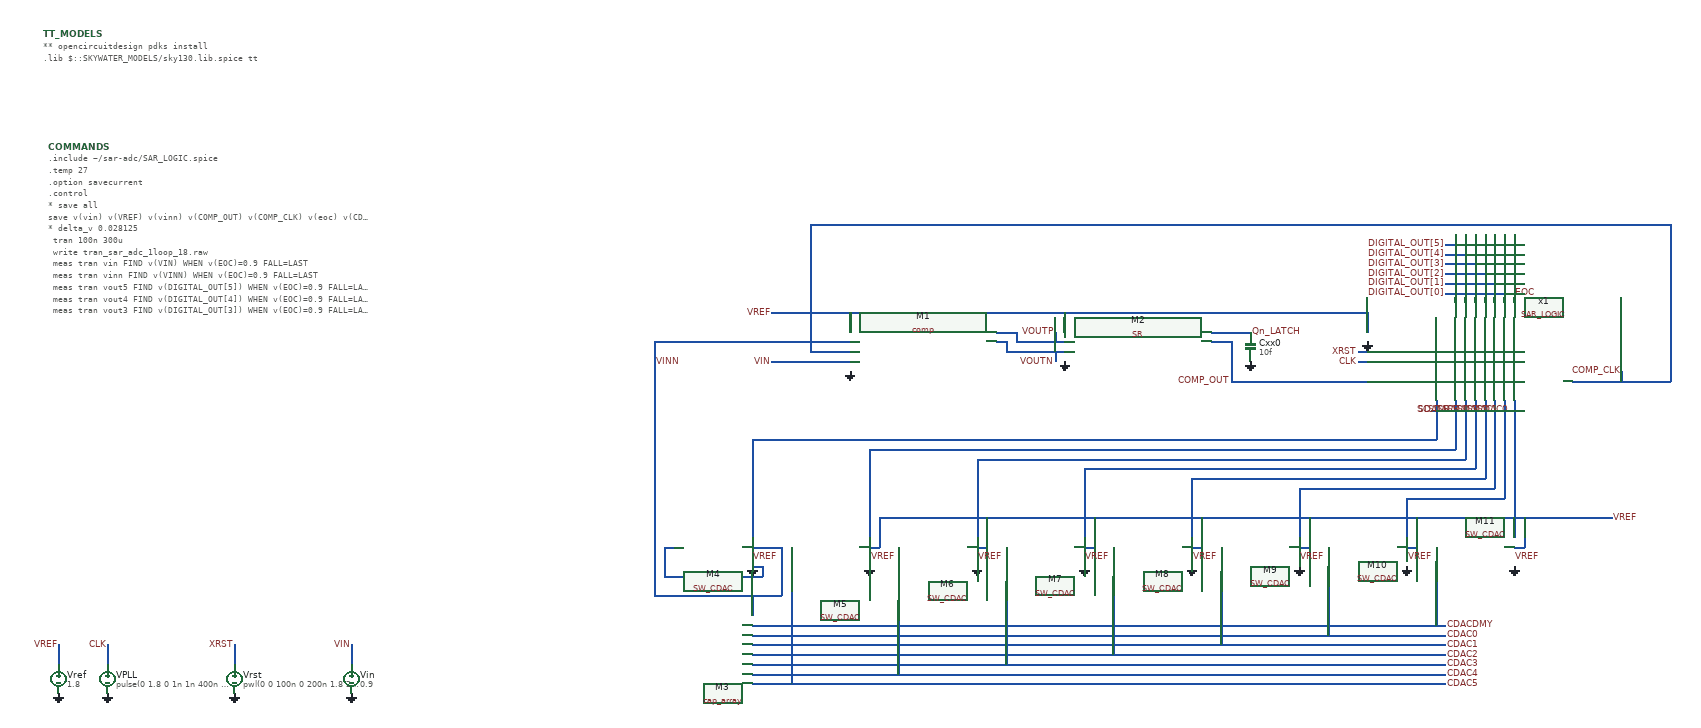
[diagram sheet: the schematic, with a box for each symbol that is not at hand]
v {xschem version=3.4.8RC file_version=1.3}
G {}
K {}
V {}
S {}
F {}
E {}
N 60 -300 60 -260 {
lab=VREF}
N 160 -300 160 -260 {
lab=CLK}
N 420 -300 420 -260 {
lab=XRST}
N 660 -300 660 -260 {
lab=VIN}
N 2460 -840 2740 -840 {
lab=COMP_OUT}
N 2720 -880 2740 -880 {
lab=CLK}
N 2720 -900 2740 -900 {
lab=XRST}
N 3040 -800 3040 -710 {
lab=SDAC0}
N 3030 -780 3040 -780 {
lab=SDAC0}
N 3020 -800 3020 -710 {
lab=SDAC1}
N 3010 -780 3020 -780 {
lab=SDAC1}
N 3000 -800 3000 -710 {
lab=SDAC2}
N 2990 -780 3000 -780 {
lab=SDAC2}
N 2980 -800 2980 -710 {
lab=SDAC3}
N 2970 -780 2980 -780 {
lab=SDAC3}
N 2960 -800 2960 -710 {
lab=SDAC4}
N 2950 -780 2960 -780 {
lab=SDAC4}
N 2940 -800 2940 -710 {
lab=SDAC5}
N 2930 -780 2940 -780 {
lab=SDAC5}
N 2920 -800 2920 -710 {
lab=SDAC6}
N 2910 -780 2920 -780 {
lab=SDAC6}
N 2880 -800 2880 -720 {
lab=SC}
N 2870 -780 2880 -780 {
lab=SC}
N 3160 -840 3360 -840 {
lab=COMP_CLK}
N 3260 -860 3260 -840 {
lab=COMP_CLK}
N 1980 -940 2020 -940 {
lab=VOUTP}
N 1980 -920 2000 -920 {
lab=VOUTN}
N 1480 -340 2900 -340 {
lab=CDACDMY}
N 1480 -320 2900 -320 {
lab=CDAC0}
N 1480 -300 2900 -300 {
lab=CDAC1}
N 1480 -280 2900 -280 {
lab=CDAC2}
N 1480 -260 2900 -260 {
lab=CDAC3}
N 1480 -240 2900 -240 {
lab=CDAC4}
N 1480 -220 2900 -220 {
lab=CDAC5}
N 1720 -700 2920 -700 {
lab=SDAC6}
N 1720 -700 1720 -520 {
lab=SDAC6}
N 1940 -680 1940 -520 {
lab=SDAC5}
N 1940 -680 2940 -680 {
lab=SDAC5}
N 2160 -660 2960 -660 {
lab=SDAC4}
N 2160 -660 2160 -520 {
lab=SDAC4}
N 2380 -640 2380 -520 {
lab=SDAC3}
N 2380 -640 2980 -640 {
lab=SDAC3}
N 2600 -620 3000 -620 {
lab=SDAC2}
N 2600 -620 2600 -520 {
lab=SDAC2}
N 2820 -600 2820 -520 {
lab=SDAC1}
N 3040 -710 3040 -520 {
lab=SDAC0}
N 1480 -720 2880 -720 {
lab=SC}
N 1480 -720 1480 -520 {
lab=SC}
N 1300 -500 1320 -500 {
lab=GND}
N 1300 -500 1300 -440 {
lab=GND}
N 1300 -440 1500 -440 {
lab=GND}
N 1500 -460 1500 -440 {
lab=GND}
N 1480 -460 1500 -460 {
lab=GND}
N 1480 -400 1480 -360 {
lab=VINN}
N 1280 -400 1480 -400 {
lab=VINN}
N 1280 -920 1280 -400 {
lab=VINN}
N 1280 -920 1680 -920 {
lab=VINN}
N 1480 -500 1540 -500 {
lab=VINN}
N 1540 -500 1540 -400 {
lab=VINN}
N 1480 -400 1540 -400 {
lab=VINN}
N 2820 -600 3020 -600 {
lab=SDAC1}
N 1600 -900 1680 -900 {
lab=COMP_CLK}
N 1600 -1160 1600 -900 {
lab=COMP_CLK}
N 1600 -1160 3360 -1160 {
lab=COMP_CLK}
N 3360 -1160 3360 -840 {
lab=COMP_CLK}
N 2420 -920 2460 -920 {
lab=COMP_OUT}
N 2460 -920 2460 -840 {
lab=COMP_OUT}
N 2420 -940 2500 -940 {
lab=Qn_LATCH}
N 1740 -560 3240 -560 {
lab=VREF}
N 1720 -500 1740 -500 {
lab=VREF}
N 1740 -560 1740 -500 {
lab=VREF}
N 1940 -500 1960 -500 {
lab=VREF}
N 1960 -560 1960 -500 {
lab=VREF}
N 2160 -500 2180 -500 {
lab=VREF}
N 2180 -560 2180 -500 {
lab=VREF}
N 2380 -500 2400 -500 {
lab=VREF}
N 2400 -560 2400 -500 {
lab=VREF}
N 2600 -500 2620 -500 {
lab=VREF}
N 2620 -560 2620 -500 {
lab=VREF}
N 2820 -500 2840 -500 {
lab=VREF}
N 2840 -560 2840 -500 {
lab=VREF}
N 3040 -500 3060 -500 {
lab=VREF}
N 3060 -560 3060 -500 {
lab=VREF}
N 1520 -880 1680 -880 {
lab=VIN}
N 2100 -900 2100 -880 {
lab=VOUTN}
N 2100 -940 2100 -920 {
lab=VOUTP}
N 2020 -940 2020 -920 {
lab=VOUTP}
N 2920 -710 2920 -700 {
lab=SDAC6}
N 2940 -710 2940 -680 {
lab=SDAC5}
N 2960 -710 2960 -660 {
lab=SDAC4}
N 2980 -710 2980 -640 {
lab=SDAC3}
N 3000 -710 3000 -620 {
lab=SDAC2}
N 3020 -710 3020 -600 {
lab=SDAC1}
N 2000 -500 2000 -260 {
lab=CDAC3}
N 1780 -500 1780 -240 {
lab=CDAC4}
N 1560 -500 1560 -220 {
lab=CDAC5}
N 2920 -1140 2920 -1000 {
lab=DIGITAL_OUT[5]}
N 2900 -1120 2920 -1120 {
lab=DIGITAL_OUT[5]}
N 2900 -1100 2940 -1100 {
lab=DIGITAL_OUT[4]}
N 2900 -1080 2960 -1080 {
lab=DIGITAL_OUT[3]}
N 2900 -1060 2980 -1060 {
lab=DIGITAL_OUT[2]}
N 2900 -1040 3000 -1040 {
lab=DIGITAL_OUT[1]}
N 2900 -1020 3020 -1020 {
lab=DIGITAL_OUT[0]}
N 2940 -1140 2940 -1000 {
lab=DIGITAL_OUT[4]}
N 2960 -1140 2960 -1000 {
lab=DIGITAL_OUT[3]}
N 2980 -1140 2980 -1000 {
lab=DIGITAL_OUT[2]}
N 3000 -1140 3000 -1000 {
lab=DIGITAL_OUT[1]}
N 3020 -1140 3020 -1000 {
lab=DIGITAL_OUT[0]}
N 3040 -1140 3040 -1000 {
lab=EOC}
N 2000 -920 2000 -900 {
lab=VOUTN}
N 2000 -900 2120 -900 {
lab=VOUTN}
N 2020 -920 2120 -920 {
lab=VOUTP}
N 2220 -500 2220 -280 {lab=CDAC2}
N 2440 -500 2440 -300 {lab=CDAC1}
N 2660 -500 2660 -320 {lab=CDAC0}
N 2880 -500 2880 -340 {lab=CDACDMY}
N 1520 -980 2740 -980 {lab=VREF}
N 2740 -980 2740 -940 {lab=VREF}
N 2120 -980 2120 -940 {lab=VREF}
N 1680 -980 1680 -940 {lab=VREF}
C {devices/vsource.sym} 60 -230 0 0 {name=Vref value=1.8 savecurrent=false}
C {devices/gnd.sym} 160 -200 0 0 {name=l2 lab=GND}
C {devices/gnd.sym} 60 -200 0 0 {name=l3 lab=GND}
C {devices/simulator_commands_shown.sym} 40 -1320 0 0 {name=COMMANDS
simulator=ngspice
only_toplevel=false 
value=".include ~/sar-adc/SAR_LOGIC.spice
.temp 27
.option savecurrent
.control
* save all
save v(vin) v(VREF) v(vinn) v(COMP_OUT) v(COMP_CLK) v(eoc) v(CDACDMY) v(CDAC0) v(CDAC1) v(CDAC2) v(CDAC3) v(CDAC4) v(CDAC5) v(digital_out[5]) v(digital_out[4]) v(digital_out[3]) v(digital_out[2]) v(digital_out[1]) v(digital_out[0])

* delta_v 0.028125

	tran 100n 300u
	write tran_sar_adc_1loop_18.raw
	meas tran vin FIND v(VIN) WHEN v(EOC)=0.9 FALL=LAST
	meas tran vinn FIND v(VINN) WHEN v(EOC)=0.9 FALL=LAST
	meas tran vout5 FIND v(DIGITAL_OUT[5]) WHEN v(EOC)=0.9 FALL=LAST
	meas tran vout4 FIND v(DIGITAL_OUT[4]) WHEN v(EOC)=0.9 FALL=LAST
	meas tran vout3 FIND v(DIGITAL_OUT[3]) WHEN v(EOC)=0.9 FALL=LAST
	meas tran vout2 FIND v(DIGITAL_OUT[2]) WHEN v(EOC)=0.9 FALL=LAST
	meas tran vout1 FIND v(DIGITAL_OUT[1]) WHEN v(EOC)=0.9 FALL=LAST
	meas tran vout0 FIND v(DIGITAL_OUT[0]) WHEN v(EOC)=0.9 FALL=LAST
	print vin >> tran_sar_adc_1loop_out_typ.txt
*	print vinn >> tran_sar_adc_1loop_out_typ.txt
	print vout5 >> tran_sar_adc_1loop_out_typ.txt
	print vout4 >> tran_sar_adc_1loop_out_typ.txt
	print vout3 >> tran_sar_adc_1loop_out_typ.txt
	print vout2 >> tran_sar_adc_1loop_out_typ.txt
	print vout1 >> tran_sar_adc_1loop_out_typ.txt
	print vout0 >> tran_sar_adc_1loop_out_typ.txt

.endc
"}
C {devices/lab_pin.sym} 160 -300 0 0 {name=p2 sig_type=std_logic lab=CLK}
C {devices/lab_pin.sym} 420 -300 0 0 {name=p9 sig_type=std_logic lab=XRST}
C {devices/gnd.sym} 420 -200 0 0 {name=l1 lab=GND}
C {devices/lab_pin.sym} 660 -300 2 1 {name=p25 sig_type=std_logic lab=VIN}
C {devices/gnd.sym} 660 -200 0 0 {name=l22 lab=GND}
C {devices/code.sym} 30 -1550 0 0 {name=TT_MODELS
only_toplevel=true
format="tcleval( @value )"
value="
** opencircuitdesign pdks install
.lib $::SKYWATER_MODELS/sky130.lib.spice tt
"
spice_ignore=false}
C {devices/vsource.sym} 160 -230 0 0 {name=VPLL value="pulse(0 1.8 0 1n 1n 400n 800n)" savecurrent=false}
C {devices/vsource.sym} 420 -230 0 0 {name=Vrst value="pwl(0 0 100n 0 200n 1.8 200n 1.8)" savecurrent=false}
C {devices/vsource.sym} 660 -230 0 0 {name=Vin value=0.9 savecurrent=false}
C {devices/lab_pin.sym} 60 -300 2 1 {name=p45 sig_type=std_logic lab=VREF}
C {devices/lab_pin.sym} 2720 -880 0 0 {name=p5 sig_type=std_logic lab=CLK}
C {devices/lab_pin.sym} 2720 -900 0 0 {name=p7 sig_type=std_logic lab=XRST}
C {devices/lab_pin.sym} 3030 -780 3 0 {name=p10 sig_type=std_logic lab=SDAC0}
C {devices/lab_pin.sym} 3010 -780 3 0 {name=p11 sig_type=std_logic lab=SDAC1}
C {devices/lab_pin.sym} 2990 -780 3 0 {name=p12 sig_type=std_logic lab=SDAC2}
C {devices/lab_pin.sym} 2970 -780 3 0 {name=p13 sig_type=std_logic lab=SDAC3}
C {devices/lab_pin.sym} 2950 -780 3 0 {name=p14 sig_type=std_logic lab=SDAC4}
C {devices/lab_pin.sym} 2930 -780 3 0 {name=p15 sig_type=std_logic lab=SDAC5}
C {devices/lab_pin.sym} 2910 -780 3 0 {name=p16 sig_type=std_logic lab=SDAC6}
C {devices/lab_pin.sym} 2870 -780 3 0 {name=p19 sig_type=std_logic lab=SC}
C {devices/lab_pin.sym} 3260 -860 0 0 {name=p20 sig_type=std_logic lab=COMP_CLK}
C {devices/gnd.sym} 1480 -460 0 1 {name=l4 lab=GND}
C {devices/gnd.sym} 1720 -460 0 1 {name=l5 lab=GND}
C {devices/gnd.sym} 1940 -460 0 1 {name=l6 lab=GND}
C {devices/gnd.sym} 2160 -460 0 1 {name=l7 lab=GND}
C {devices/gnd.sym} 2380 -460 0 1 {name=l8 lab=GND}
C {devices/gnd.sym} 2600 -460 0 1 {name=l9 lab=GND}
C {devices/gnd.sym} 2820 -460 0 1 {name=l10 lab=GND}
C {devices/gnd.sym} 3040 -460 0 1 {name=l11 lab=GND}
C {devices/gnd.sym} 2740 -920 0 1 {name=l16 lab=GND}
C {devices/gnd.sym} 1680 -860 0 1 {name=l18 lab=GND}
C {devices/gnd.sym} 2120 -880 0 1 {name=l19 lab=GND}
C {devices/capa.sym} 2500 -910 0 0 {name=Cxx0
m=1
value=10f
footprint=1206
device="ceramic capacitor"}
C {devices/gnd.sym} 2500 -880 0 1 {name=l20 lab=GND}
C {devices/lab_pin.sym} 1520 -880 0 0 {name=p26 sig_type=std_logic lab=VIN}
C {devices/lab_pin.sym} 2100 -880 0 0 {name=p27 sig_type=std_logic lab=VOUTN}
C {devices/lab_pin.sym} 2100 -940 2 1 {name=p28 sig_type=std_logic lab=VOUTP}
C {devices/lab_pin.sym} 2900 -280 0 1 {name=p29 sig_type=std_logic lab=CDAC2}
C {devices/lab_pin.sym} 2900 -300 0 1 {name=p30 sig_type=std_logic lab=CDAC1}
C {devices/lab_pin.sym} 2900 -320 0 1 {name=p31 sig_type=std_logic lab=CDAC0}
C {devices/lab_pin.sym} 2900 -340 0 1 {name=p32 sig_type=std_logic lab=CDACDMY}
C {devices/lab_pin.sym} 2900 -260 0 1 {name=p33 sig_type=std_logic lab=CDAC3}
C {devices/lab_pin.sym} 2900 -240 0 1 {name=p34 sig_type=std_logic lab=CDAC4}
C {devices/lab_pin.sym} 2900 -220 0 1 {name=p35 sig_type=std_logic lab=CDAC5}
C {devices/lab_pin.sym} 1280 -880 0 1 {name=p36 sig_type=std_logic lab=VINN}
C {devices/lab_pin.sym} 3240 -560 2 0 {name=p37 sig_type=std_logic lab=VREF}
C {devices/lab_pin.sym} 2500 -940 2 0 {name=p38 sig_type=std_logic lab=Qn_LATCH}
C {devices/lab_pin.sym} 2460 -840 0 0 {name=p39 sig_type=std_logic lab=COMP_OUT}
C {devices/lab_pin.sym} 2900 -1120 0 0 {name=p18 sig_type=std_logic lab=DIGITAL_OUT[5]}
C {devices/lab_pin.sym} 2900 -1100 0 0 {name=p21 sig_type=std_logic lab=DIGITAL_OUT[4]}
C {devices/lab_pin.sym} 2900 -1080 0 0 {name=p40 sig_type=std_logic lab=DIGITAL_OUT[3]}
C {devices/lab_pin.sym} 2900 -1060 0 0 {name=p41 sig_type=std_logic lab=DIGITAL_OUT[2]}
C {devices/lab_pin.sym} 2900 -1040 0 0 {name=p42 sig_type=std_logic lab=DIGITAL_OUT[1]}
C {devices/lab_pin.sym} 2900 -1020 0 0 {name=p43 sig_type=std_logic lab=DIGITAL_OUT[0]}
C {devices/lab_pin.sym} 3040 -1020 2 0 {name=p17 sig_type=std_logic lab=EOC}
C {comp.sym} 1830 -900 0 0 {name=M1
spiceprefix=X}
C {SR.sym} 2270 -910 0 0 {name=M2
spiceprefix=X
}
C {SAR_LOGIC.sym} 2950 -890 0 0 {name=x1 prefix=SAR_LOGIC}
C {cap_array.sym} 1330 -290 0 0 {name=M3
spiceprefix=X}
C {SW_CDAC.sym} 1480 -520 0 1 {name=M4
spiceprefix=X}
C {SW_CDAC.sym} 1720 -520 0 1 {name=M5
spiceprefix=X}
C {SW_CDAC.sym} 1940 -520 0 1 {name=M6
spiceprefix=X}
C {SW_CDAC.sym} 2160 -520 0 1 {name=M7
spiceprefix=X}
C {SW_CDAC.sym} 2380 -520 0 1 {name=M8
spiceprefix=X}
C {SW_CDAC.sym} 2600 -520 0 1 {name=M9
spiceprefix=X}
C {SW_CDAC.sym} 2820 -520 0 1 {name=M10
spiceprefix=X}
C {SW_CDAC.sym} 3040 -520 0 1 {name=M11
spiceprefix=X}
C {devices/lab_pin.sym} 1520 -980 2 1 {name=p1 sig_type=std_logic lab=VREF}
C {devices/lab_pin.sym} 3040 -480 2 0 {name=p3 sig_type=std_logic lab=VREF}
C {devices/lab_pin.sym} 2820 -480 2 0 {name=p4 sig_type=std_logic lab=VREF}
C {devices/lab_pin.sym} 2600 -480 2 0 {name=p6 sig_type=std_logic lab=VREF}
C {devices/lab_pin.sym} 2380 -480 2 0 {name=p8 sig_type=std_logic lab=VREF}
C {devices/lab_pin.sym} 2160 -480 2 0 {name=p22 sig_type=std_logic lab=VREF}
C {devices/lab_pin.sym} 1940 -480 2 0 {name=p23 sig_type=std_logic lab=VREF}
C {devices/lab_pin.sym} 1720 -480 2 0 {name=p24 sig_type=std_logic lab=VREF}
C {devices/lab_pin.sym} 1480 -480 2 0 {name=p44 sig_type=std_logic lab=VREF}
